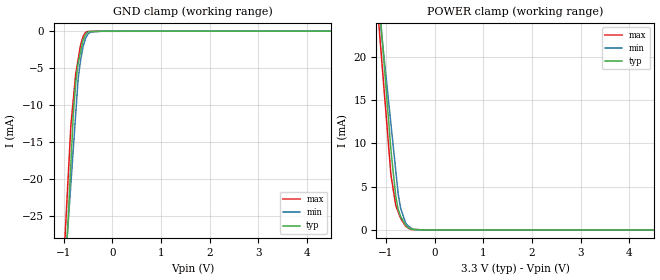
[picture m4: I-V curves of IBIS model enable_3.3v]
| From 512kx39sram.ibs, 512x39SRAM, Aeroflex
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[Model] enable_3.3v
Model_type Input
Vinl = 800.000mV
Vinh = 2.20000V
C_comp 1.50000pF 1.44000pF 1.56000pF
| variable typ   min   max
[Voltage Range] 3.30000V 3.00000V 3.60000V
[POWER Clamp Reference] 3.30000V 3.00000V 3.60000V
[GND Clamp Reference] 0.00000V 0.00000V 0.00000V
[Temperature Range]   25   105   -55
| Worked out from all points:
|   GND clamp passes 1 mA (typ) near -0.58 V on its own axis
|   POWER clamp passes 1 mA (typ) near -0.64 V on its own axis
[GND Clamp]
-3.3V     -343.8mA   -253.6mA   -320mA
-850mV    -17.92mA   -20.69mA   -12.79mA
-800mV    -11.27mA   -15.93mA   -9.279mA
-750mV    -7.022mA   -11.18mA   -5.768mA
-700mV    -4.322mA   -6.425mA   -3.807mA
-650mV    -2.782mA   -3.918mA   -1.846mA
-600mV    -1.242mA   -2.113mA   -708.7uA
-550mV    -454.3uA   -997.4uA   -177.8uA
-500mV    -118.4uA   -386.8uA   -29.63uA
-450mV    -23.64uA   -113.8uA   -24.11uA
-225mV    -2.167uA   -2.758uA   -2.004uA
6.6V      6.77uA     20.76uA    4.73uA
[POWER Clamp]
-3.3V     180.4mA    142.1mA    174.2mA
-1.15V    27.04mA    25.76mA    23.83mA
-1.1V     23.47mA    23.05mA    20.34mA
-1V       16.34mA    17.64mA    13.34mA
-900mV    9.205mA    12.23mA    6.348mA
-800mV    3.85mA     6.814mA    2.809mA
-750mV    2.365mA    4.108mA    2.079mA
-700mV    1.552mA    2.497mA    1.348mA
-600mV    596.8uA    837.1uA    437.6uA
-500mV    118.7uA    285.7uA    58.11uA
-350mV    47.47uA    0A         36.32uA
6.6V      0A         0A         0A
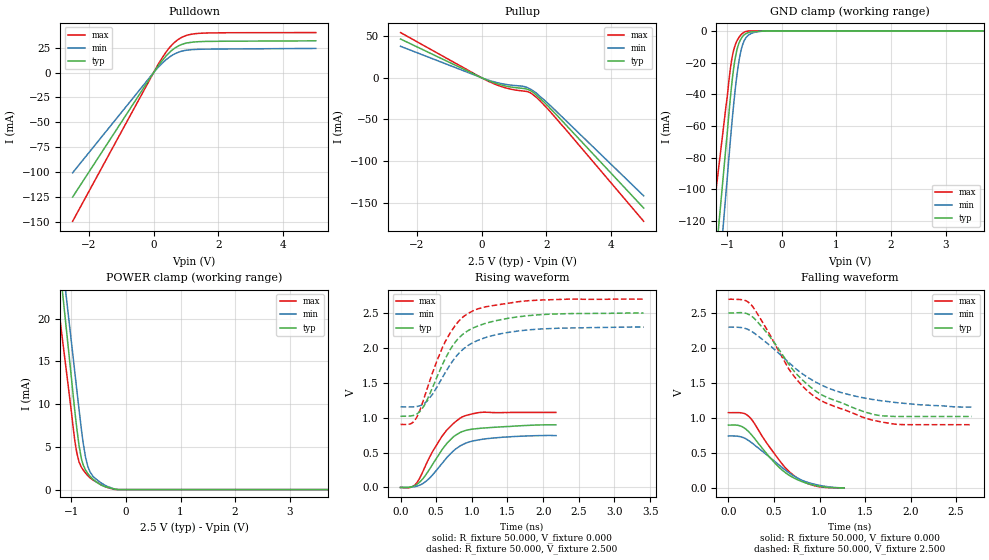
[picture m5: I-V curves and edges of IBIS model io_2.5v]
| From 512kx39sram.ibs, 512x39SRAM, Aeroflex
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[Model]   io_2.5v
Model_type I/O
Vinl=8.000E-01
Vinh=2.200E+00
Vref=1.250E+00
Rref=5.000E+01
Cref=4.000E-11
Vmeas=1.250E+00
C_comp   9.150E-13   9.050E-13   9.240E-13
[Voltage Range]   2.500E+00   2.300E+00   2.700E+00
[POWER Clamp Reference]   2.500E+00   2.300E+00   2.700E+00
[GND Clamp Reference]   0.000E+00   0.000E+00   0.000E+00
[Pullup Reference]   2.500E+00   2.300E+00   2.700E+00
[Pulldown Reference]   0.000E+00   0.000E+00   0.000E+00
[Temperature Range]   25   105   -55
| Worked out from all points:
|   slope of the pulldown table from 0 to 0.375 V, typ, clamps not added: 23 ohm
|   slope of the pullup table from 0 to 0.375 V, typ, clamps not added: 64.2 ohm
|   GND clamp passes 1 mA (typ) near -0.60 V on its own axis
|   POWER clamp passes 1 mA (typ) near -0.56 V on its own axis
|   rising waveform, R_fixture 50.000, V_fixture 0.000: 20-80 % time 380ps typ, 415ps min, 379ps max; typ from 0 V to 0.898 V
|   falling waveform, R_fixture 50.000, V_fixture 0.000: 20-80 % time 389ps typ, 442ps min, 368ps max; typ from 0.898 V to 0 V
|   rising waveform, R_fixture 50.000, V_fixture 2.500: 20-80 % time 484ps typ, 529ps min, 457ps max; typ from 1.02 V to 2.5 V
|   falling waveform, R_fixture 50.000, V_fixture 2.500: 20-80 % time 615ps typ, 762ps min, 607ps max; typ from 2.5 V to 1.02 V
[GND Clamp]
-2.5V     -629.6mA   -708.7mA   -475.9mA
-1.02V    -71.93mA   -101.3mA   -46.96mA
-940mV    -41.52mA   -68.31mA   -23.36mA
-900mV    -28.6mA    -52.92mA   -14.98mA
-860mV    -18.68mA   -39.18mA   -9.646mA
-820mV    -11.79mA   -27.45mA   -6.228mA
-780mV    -7.389mA   -18.14mA   -3.892mA
-740mV    -4.639mA   -11.45mA   -2.227mA
-680mV    -2.287mA   -5.651mA   -705.7uA
-540mV    -617.8uA   -1.371mA   -37.4uA
-260mV    0A         0A         0A
5V        0A         0A         0A
[Power Clamp]
-2.5V     105.2mA    102.2mA    86.75mA
-1V       13.15mA    17.31mA    9.146mA
-960mV    10.61mA    15.07mA    6.892mA
-920mV    8.245mA    12.79mA    5.022mA
-860mV    5.186mA    9.424mA    3.253mA
-800mV    3.227mA    6.228mA    2.46mA
-740mV    2.288mA    3.782mA    1.934mA
-700mV    1.884mA    2.739mA    1.645mA
-660mV    1.571mA    2.09mA     1.389mA
-460mV    548.1uA    805uA      585uA
-140mV    0A         0A         0A
5V        0A         0A         0A
[Pullup]
-2.5V     46.59mA    37.83mA    54.34mA
240mV     -3.905mA   -3.273mA   -4.776mA
800mV     -10.39mA   -8.317mA   -12.73mA
1.32V     -13.02mA   -10.63mA   -16.09mA
1.44V     -14.29mA   -12.34mA   -17.01mA
1.56V     -16.78mA   -14.94mA   -19.45mA
1.78V     -24.1mA    -21.68mA   -26.79mA
2.14V     -37.69mA   -34.1mA    -41.76mA
5V        -156.7mA   -142mA     -172.6mA
[Pulldown]
-2.5V     -125mA     -100.6mA   -149.3mA
140mV     6.695mA    5.251mA    8.206mA
460mV     19.25mA    14.88mA    23.85mA
680mV     25.11mA    19.2mA     31.23mA
840mV     27.83mA    21.22mA    34.88mA
980mV     29.34mA    22.27mA    36.91mA
1.4V      30.99mA    23.34mA    39.35mA
5V        31.81mA    24.21mA    40.12mA
[Rising Waveform]
R_fixture = 50.000
V_fixture = 0.000
V_fixture_min = 0.000
V_fixture_max = 0.000
|  time   V(typ)   V(min)   V(max)
0s        0V         0V         0V
140ps     6.33mV     3.616mV    425.6uV
220ps     38.16mV    15.9mV     56.72mV
380ps     218.7mV    108.4mV    377.6mV
580ps     538.3mV    341mV      731.6mV
730ps     715.1mV    513.2mV    905.5mV
870ps     802.6mV    614mV      1.013V
1.09ns    845.5mV    680.8mV    1.072V
1.24ns    857.3mV    702.6mV    1.077V
2.18ns    897.8mV    743.2mV    1.076V
[Falling Waveform]
R_fixture = 50.000
V_fixture = 0.000
V_fixture_min = 0.000
V_fixture_max = 0.000
|  time   V(typ)   V(min)   V(max)
0s        897.8mV    743.2mV    1.076V
130ps     886.1mV    732.3mV    1.075V
180ps     851.6mV    709.3mV    1.06V
230ps     792.7mV    669.4mV    1.015V
540ps     314mV      343.8mV    427mV
650ps     194.8mV    230.6mV    254.1mV
760ps     115.2mV    138.9mV    138.7mV
860ps     65.82mV    83.43mV    67.77mV
970ps     28.53mV    44.13mV    22.93mV
1.27ns    0V         0V         0V
[Rising Waveform]
R_fixture = 50.000
V_fixture = 2.500
V_fixture_min = 2.300
V_fixture_max = 2.700
|  time   V(typ)   V(min)   V(max)
0s        1.021V     1.156V     903.5mV
180ps     1.032V     1.156V     938.7mV
290ps     1.11V      1.178V     1.157V
450ps     1.434V     1.338V     1.648V
630ps     1.852V     1.651V     2.096V
770ps     2.087V     1.867V     2.326V
970ps     2.261V     2.05V      2.508V
1.32ns    2.387V     2.185V     2.611V
1.78ns    2.462V     2.258V     2.676V
3.41ns    2.5V       2.3V       2.7V
[Falling Waveform]
R_fixture = 50.000
V_fixture = 2.500
V_fixture_min = 2.300
V_fixture_max = 2.700
|  time   V(typ)   V(min)   V(max)
0s        2.5V       2.3V       2.7V
170ps     2.503V     2.286V     2.687V
250ps     2.46V      2.242V     2.619V
430ps     2.205V     2.064V     2.248V
690ps     1.719V     1.762V     1.65V
850ps     1.499V     1.598V     1.408V
1.02ns    1.333V     1.472V     1.245V
1.29ns    1.191V     1.345V     1.109V
1.66ns    1.035V     1.249V     948.4mV
2.67ns    1.021V     1.156V     903.5mV
[Ramp]
dV/dt_r   5.3766E-01/3.7963E-10   4.4550E-01/4.1377E-10   6.4637E-01/3.7771E-10
dV/dt_f   8.8739E-01/6.1363E-10   6.8662E-01/7.6244E-10   1.0779E+00/6.0748E-10
R_load = 50
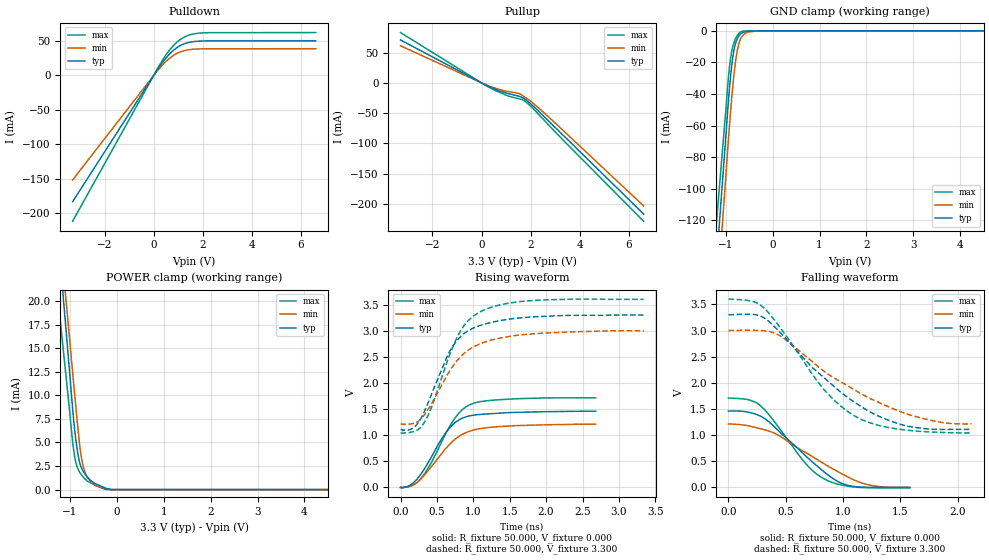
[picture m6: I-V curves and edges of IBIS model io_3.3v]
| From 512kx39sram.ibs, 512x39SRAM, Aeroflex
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[Model]   io_3.3v
Model_type I/O
Vinl=8.000E-01
Vinh=2.200E+00
Vref=1.650E+00
Rref=5.000E+01
Cref=4.000E-11
Vmeas=1.650E+00
C_comp   9.150E-13   9.050E-13   9.240E-13
[Voltage Range]   3.300E+00   3.000E+00   3.600E+00
[POWER Clamp Reference]   3.300E+00   3.000E+00   3.600E+00
[GND Clamp Reference]   0.000E+00   0.000E+00   0.000E+00
[Pullup Reference]   3.300E+00   3.000E+00   3.600E+00
[Pulldown Reference]   0.000E+00   0.000E+00   0.000E+00
[Temperature Range]   25   105   -55
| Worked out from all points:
|   slope of the pulldown table from 0 to 0.495 V, typ, clamps not added: 19.8 ohm
|   slope of the pullup table from 0 to 0.495 V, typ, clamps not added: 52.1 ohm
|   GND clamp passes 1 mA (typ) near -0.63 V on its own axis
|   POWER clamp passes 1 mA (typ) near -0.56 V on its own axis
|   rising waveform, R_fixture 50.000, V_fixture 0.000: 20-80 % time 396ps typ, 463ps min, 406ps max; typ from 0 V to 1.46 V
|   falling waveform, R_fixture 50.000, V_fixture 0.000: 20-80 % time 441ps typ, 547ps min, 364ps max; typ from 1.46 V to 0 V
|   rising waveform, R_fixture 50.000, V_fixture 3.300: 20-80 % time 450ps typ, 534ps min, 437ps max; typ from 1.11 V to 3.3 V
|   falling waveform, R_fixture 50.000, V_fixture 3.300: 20-80 % time 663ps typ, 765ps min, 541ps max; typ from 3.3 V to 1.11 V
[GND Clamp]
-3.3V     -988.4mA   -1.048A    -877.2mA
-1.02V    -76.29mA   -101.8mA   -58.36mA
-960mV    -51.87mA   -76.75mA   -36.04mA
-920mV    -36.73mA   -60.49mA   -23.26mA
-860mV    -19.31mA   -38.87mA   -11.46mA
-820mV    -11.82mA   -26.92mA   -7.18mA
-760mV    -5.487mA   -13.71mA   -3.272mA
-720mV    -3.245mA   -8.194mA   -1.629mA
-660mV    -1.452mA   -3.86mA    -380uA
-540mV    -345.9uA   -991.4uA   -14.19uA
-260mV    0A         0A         0A
6.6V      0A         0A         0A
[Power Clamp]
-3.3V     147.5mA    140.5mA    119.1mA
-1V       12.18mA    15.69mA    8.091mA
-940mV    8.572mA    12.43mA    5.067mA
-900mV    6.472mA    10.28mA    3.566mA
-860mV    4.833mA    8.146mA    2.653mA
-820mV    3.553mA    6.088mA    2.106mA
-760mV    2.387mA    3.574mA    1.611mA
-720mV    1.975mA    2.542mA    1.371mA
-640mV    1.413mA    1.411mA    954.2uA
-440mV    592.1uA    426uA      403.2uA
-120mV    0A         0A         0A
6.6V      0A         0A         0A
[Pullup]
-3.3V     70.99mA    61.36mA    83.25mA
260mV     -5.303mA   -4.365mA   -6.209mA
1.04V     -17.11mA   -13.82mA   -21.03mA
1.4V      -20.89mA   -16.34mA   -25.01mA
1.62V     -23.52mA   -19.63mA   -27.17mA
1.9V      -31.16mA   -27.36mA   -34.86mA
2.58V     -57.16mA   -50.75mA   -63.09mA
3.34V     -87.24mA   -79.43mA   -95.45mA
6.6V      -217mA     -203.5mA   -228.9mA
[Pulldown]
-3.3V     -183.2mA   -151.6mA   -211.6mA
160mV     8.754mA    7.117mA    10.31mA
420mV     21.64mA    17.4mA     25.59mA
620mV     30.13mA    24.18mA    35.76mA
800mV     36.3mA     28.97mA    43.3mA
1.02V     42.13mA    33.3mA     50.53mA
1.42V     47.89mA    37.33mA    58.37mA
2.02V     50.06mA    38.67mA    61.82mA
6.6V      50.33mA    38.84mA    62.29mA
[Rising Waveform]
R_fixture = 50.000
V_fixture = 0.000
V_fixture_min = 0.000
V_fixture_max = 0.000
|  time   V(typ)   V(min)   V(max)
0s        0V         0V         0V
130ps     41.89mV    24.28mV    23.34mV
280ps     255mV      164.6mV    168.1mV
420ps     572.3mV    392.9mV    467mV
630ps     1.065V     759.2mV    1.059V
810ps     1.299V     983.7mV    1.435V
960ps     1.374V     1.082V     1.589V
1.11ns    1.4V       1.13V      1.646V
1.53ns    1.435V     1.179V     1.693V
2.68ns    1.46V      1.211V     1.716V
[Falling Waveform]
R_fixture = 50.000
V_fixture = 0.000
V_fixture_min = 0.000
V_fixture_max = 0.000
|  time   V(typ)   V(min)   V(max)
0s        1.46V      1.211V     1.707V
180ps     1.436V     1.174V     1.674V
280ps     1.362V     1.121V     1.561V
440ps     1.075V     991.9mV    1.142V
680ps     590mV      658.2mV    439.6mV
760ps     432.7mV    551.5mV    271.3mV
850ps     268.6mV    429.6mV    145.4mV
990ps     75.53mV    259mV      43.17mV
1.2ns     2.84mV     59.92mV    -5.514mV
1.58ns    0V         0V         -8.921mV
[Rising Waveform]
R_fixture = 50.000
V_fixture = 3.300
V_fixture_min = 3.000
V_fixture_max = 3.600
|  time   V(typ)   V(min)   V(max)
0s        1.109V     1.213V     1.041V
180ps     1.144V     1.226V     1.069V
320ps     1.432V     1.376V     1.228V
440ps     1.836V     1.636V     1.584V
700ps     2.664V     2.285V     2.631V
870ps     2.943V     2.563V     3.093V
1.08ns    3.094V     2.742V     3.352V
1.37ns    3.194V     2.86V      3.496V
1.72ns    3.254V     2.929V     3.568V
3.34ns    3.3V       3V         3.6V
[Falling Waveform]
R_fixture = 50.000
V_fixture = 3.300
V_fixture_min = 3.000
V_fixture_max = 3.600
|  time   V(typ)   V(min)   V(max)
0s        3.3V       3V         3.6V
200ps     3.31V      3.005V     3.563V
310ps     3.242V     2.996V     3.43V
450ps     2.964V     2.898V     3.058V
830ps     2.105V     2.226V     1.878V
1.12ns    1.599V     1.838V     1.342V
1.32ns    1.352V     1.614V     1.18V
1.55ns    1.177V     1.408V     1.096V
1.86ns    1.108V     1.241V     1.051V
2.12ns    1.109V     1.213V     1.041V
[Ramp]
dV/dt_r   8.7516E-01/3.9385E-10   7.2648E-01/4.6193E-10   1.0295E+00/4.0315E-10
dV/dt_f   1.3144E+00/6.6260E-10   1.0724E+00/7.6492E-10   1.5353E+00/5.4080E-10
R_load = 50
